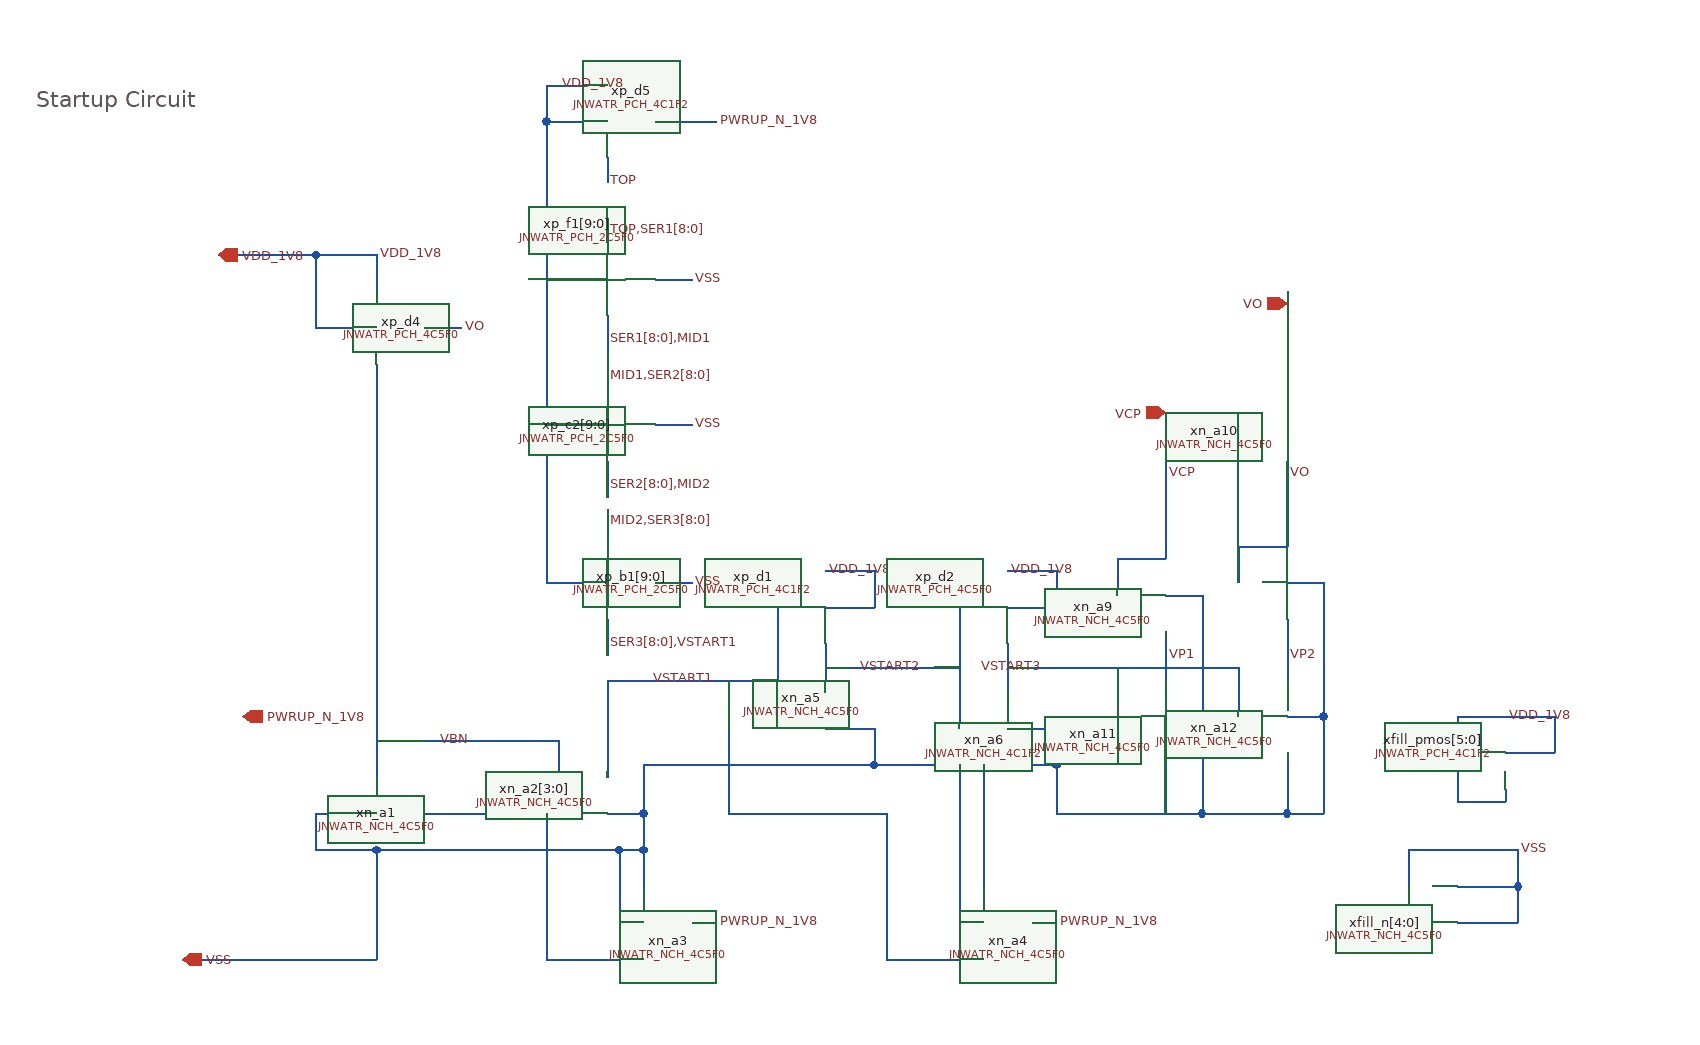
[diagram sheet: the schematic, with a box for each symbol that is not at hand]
v {xschem version=3.4.7 file_version=1.2}
G {}
K {}
V {}
S {}
E {}
T {Startup Circuit} -180 -740 0 0 1 1 {}
N 290 -140 320 -140 {lab=VSS}
N 320 -140 320 -110 {lab=VSS}
N 250 -200 250 -140 {lab=VBN}
N 290 -240 290 -170 {lab=VSTART1}
N 470 -280 470 -240 {lab=VSTART2}
N 470 -210 510 -210 {lab=VSS}
N 510 -210 510 -180 {lab=VSS}
N 470 -180 510 -180 {lab=VSS}
N 320 -180 470 -180 {lab=VSS}
N 320 -180 320 -140 {lab=VSS}
N 430 -310 430 -210 {lab=VSTART1}
N 290 -250 430 -250 {lab=VSTART1}
N 470 -310 510 -310 {lab=VDD_1V8}
N 510 -340 510 -310 {lab=VDD_1V8}
N 470 -340 510 -340 {lab=VDD_1V8}
N 620 -280 620 -240 {lab=VSTART3}
N 620 -210 660 -210 {lab=VSS}
N 660 -210 660 -180 {lab=VSS}
N 620 -180 660 -180 {lab=VSS}
N 580 -310 580 -210 {lab=VSTART2}
N 620 -310 660 -310 {lab=VDD_1V8}
N 660 -340 660 -310 {lab=VDD_1V8}
N 620 -340 660 -340 {lab=VDD_1V8}
N 470 -260 580 -260 {lab=VSTART2}
N 660 -140 730 -140 {lab=VSS}
N 730 -140 760 -140 {lab=VSS}
N 850 -190 850 -140 {lab=VSS}
N 780 -140 850 -140 {lab=VSS}
N 850 -220 880 -220 {lab=VSS}
N 880 -220 880 -140 {lab=VSS}
N 850 -140 880 -140 {lab=VSS}
N 760 -140 780 -140 {lab=VSS}
N 690 -260 810 -260 {lab=VSTART3}
N 810 -260 810 -220 {lab=VSTART3}
N 660 -180 660 -140 {lab=VSS}
N 510 -180 620 -180 {lab=VSS}
N 240 -430 240 -380 {lab=VDD_1V8}
N 290 -680 290 -660 {lab=TOP}
N 330 -330 360 -330 {lab=VSS}
N 620 -260 690 -260 {lab=VSTART3}
N 140 -140 250 -140 {lab=VBN}
N 100 -510 100 -170 {lab=VBN}
N 50 -600 50 -540 {lab=VDD_1V8}
N 100 -600 100 -570 {lab=VDD_1V8}
N 100 -200 250 -200 {lab=VBN}
N 750 -220 780 -220 {lab=VSS}
N 780 -220 780 -140 {lab=VSS}
N 750 -190 750 -140 {lab=VSS}
N 710 -260 710 -220 {lab=VSTART3}
N 750 -420 750 -410 {lab=VCP}
N 50 -540 100 -540 {lab=VDD_1V8}
N 50 -600 100 -600 {lab=VDD_1V8}
N 70 -140 100 -140 {lab=VSS}
N 50 -140 70 -140 {lab=VSS}
N 50 -140 50 -110 {lab=VSS}
N 300 -110 300 -50 {lab=VSS}
N 300 -50 320 -50 {lab=VSS}
N 320 -110 320 -80 {lab=VSS}
N 360 -50 380 -50 {lab=PWRUP_N_1V8}
N 240 -20 320 -20 {lab=VBN}
N 240 -140 240 -20 {lab=VBN}
N 240 -710 290 -710 {lab=VDD_1V8}
N 240 -710 240 -680 {lab=VDD_1V8}
N 240 -740 240 -710 {lab=VDD_1V8}
N 240 -740 290 -740 {lab=VDD_1V8}
N 330 -710 380 -710 {lab=PWRUP_N_1V8}
N 580 -110 580 -50 {lab=VSS}
N 580 -50 600 -50 {lab=VSS}
N 600 -110 600 -80 {lab=VSS}
N 640 -50 660 -50 {lab=PWRUP_N_1V8}
N 520 -20 600 -20 {lab=VSTART1}
N 520 -140 520 -20 {lab=VSTART1}
N 600 -180 600 -110 {lab=VSS}
N 580 -180 580 -110 {lab=VSS}
N 390 -140 520 -140 {lab=VSTART1}
N 390 -250 390 -140 {lab=VSTART1}
N 750 -290 750 -250 {lab=VP1}
N 750 -320 780 -320 {lab=VSS}
N 780 -320 780 -220 {lab=VSS}
N 710 -350 710 -320 {lab=VCP}
N 710 -350 750 -350 {lab=VCP}
N 750 -410 750 -350 {lab=VCP}
N 850 -330 880 -330 {lab=VSS}
N 810 -360 810 -330 {lab=VO}
N 810 -360 850 -360 {lab=VO}
N 850 -300 850 -250 {lab=VP2}
N 880 -330 880 -220 {lab=VSS}
N 850 -420 850 -360 {lab=VO}
N -30 -600 30 -600 {lab=VDD_1V8}
N 850 -560 850 -420 {lab=VO}
N 50 -110 100 -110 {lab=VSS}
N 100 -110 100 -20 {lab=VSS}
N -60 -20 100 -20 {lab=VSS}
N 30 -600 50 -600 {lab=VDD_1V8}
N 850 -570 850 -560 {lab=VO}
N 270 -330 290 -330 {lab=VDD_1V8}
N 290 -390 290 -360 {lab=MID2,SER3[8:0]}
N 290 -300 290 -270 {lab=SER3[8:0],VSTART1}
N 290 -250 290 -240 {lab=VSTART1}
N 240 -380 240 -330 {lab=VDD_1V8}
N 240 -330 270 -330 {lab=VDD_1V8}
N 290 -110 300 -110 {lab=VSS}
N 100 -110 290 -110 {lab=VSS}
N 750 -470 750 -420 {lab=VCP}
N 140 -540 170 -540 {lab=VO}
N 240 -540 240 -430 {lab=VDD_1V8}
N 290 -510 290 -490 {lab=MID1,SER2[8:0]}
N 290 -430 290 -400 {lab=SER2[8:0],MID2}
N 330 -460 360 -460 {lab=VSS}
N 300 -110 320 -110 {lab=VSS}
N 240 -650 240 -540 {lab=VDD_1V8}
N 240 -680 240 -650 {lab=VDD_1V8}
N 290 -630 290 -610 {lab=TOP,SER1[8:0]}
N 290 -550 290 -520 {lab=SER1[8:0],MID1}
N 330 -580 360 -580 {lab=VSS}
N 240 -460 290 -460 {lab=VDD_1V8}
N 240 -580 290 -580 {lab=VDD_1V8}
N 1030 -190 1070 -190 {lab=VDD_1V8}
N 1070 -220 1070 -190 {lab=VDD_1V8}
N 1030 -220 1070 -220 {lab=VDD_1V8}
N 1030 -160 1030 -150 {lab=VDD_1V8}
N 990 -150 1030 -150 {lab=VDD_1V8}
N 990 -190 990 -150 {lab=VDD_1V8}
N 990 -220 990 -190 {lab=VDD_1V8}
N 990 -220 1030 -220 {lab=VDD_1V8}
N 990 -50 1040 -50 {lab=VSS}
N 1040 -80 1040 -50 {lab=VSS}
N 990 -80 1040 -80 {lab=VSS}
N 1040 -110 1040 -80 {lab=VSS}
N 990 -110 1040 -110 {lab=VSS}
N 950 -110 950 -80 {lab=VSS}
N 950 -110 990 -110 {lab=VSS}
C {JNW_ATR_SKY130A/JNWATR_NCH_4C5F0.sym} 250 -140 0 0 {name=xn_a2[3:0]}
C {JNW_ATR_SKY130A/JNWATR_NCH_4C5F0.sym} 430 -210 0 0 {name=xn_a5}
C {JNW_ATR_SKY130A/JNWATR_PCH_4C1F2.sym} 430 -310 0 0 {name=xp_d1}
C {devices/lab_wire.sym} 470 -340 0 1 {name=p43 sig_type=std_logic lab=VDD_1V8}
C {devices/lab_wire.sym} 380 -250 0 0 {name=p37 sig_type=std_logic lab=VSTART1}
C {JNW_ATR_SKY130A/JNWATR_NCH_4C1F2.sym} 580 -210 0 0 {name=xn_a6}
C {JNW_ATR_SKY130A/JNWATR_PCH_4C5F0.sym} 580 -310 0 0 {name=xp_d2}
C {devices/lab_wire.sym} 620 -340 0 1 {name=p44 sig_type=std_logic lab=VDD_1V8}
C {JNW_ATR_SKY130A/JNWATR_NCH_4C5F0.sym} 810 -220 0 0 {name=xn_a12}
C {devices/lab_wire.sym} 850 -420 0 1 {name=p52 sig_type=std_logic lab=VO}
C {devices/lab_wire.sym} 550 -260 0 0 {name=p54 sig_type=std_logic lab=VSTART2}
C {devices/lab_wire.sym} 650 -260 0 0 {name=p58 sig_type=std_logic lab=VSTART3}
C {devices/lab_wire.sym} 360 -330 0 1 {name=p36 sig_type=std_logic lab=VSS}
C {JNW_ATR_SKY130A/JNWATR_PCH_4C5F0.sym} 140 -540 0 1 {name=xp_d4}
C {JNW_ATR_SKY130A/JNWATR_NCH_4C5F0.sym} 140 -140 0 1 {name=xn_a1}
C {devices/lab_wire.sym} 170 -540 0 1 {name=p6 sig_type=std_logic lab=VO}
C {JNW_ATR_SKY130A/JNWATR_NCH_4C5F0.sym} 710 -220 0 0 {name=xn_a11}
C {devices/lab_wire.sym} 750 -420 0 1 {name=p56 sig_type=std_logic lab=VCP}
C {devices/lab_wire.sym} 100 -600 0 1 {name=p61 sig_type=std_logic lab=VDD_1V8}
C {JNW_ATR_SKY130A/JNWATR_NCH_4C5F0.sym} 360 -50 2 0 {name=xn_a3}
C {devices/lab_wire.sym} 380 -50 2 0 {name=p64 sig_type=std_logic lab=PWRUP_N_1V8}
C {JNW_ATR_SKY130A/JNWATR_PCH_4C1F2.sym} 330 -710 0 1 {name=xp_d5}
C {devices/lab_wire.sym} 250 -740 0 1 {name=p38 sig_type=std_logic lab=VDD_1V8}
C {devices/lab_wire.sym} 380 -710 0 1 {name=p65 sig_type=std_logic lab=PWRUP_N_1V8}
C {JNW_ATR_SKY130A/JNWATR_NCH_4C5F0.sym} 640 -50 2 0 {name=xn_a4}
C {devices/lab_wire.sym} 660 -50 2 0 {name=p66 sig_type=std_logic lab=PWRUP_N_1V8}
C {JNW_ATR_SKY130A/JNWATR_NCH_4C5F0.sym} 710 -320 0 0 {name=xn_a9}
C {JNW_ATR_SKY130A/JNWATR_NCH_4C5F0.sym} 810 -330 0 0 {name=xn_a10}
C {devices/ipin.sym} -30 -600 2 1 {name=p4 lab=VDD_1V8}
C {devices/ipin.sym} -60 -20 2 1 {name=p5 lab=VSS}
C {devices/ipin.sym} -10 -220 2 1 {name=p9 lab=PWRUP_N_1V8}
C {devices/ipin.sym} 850 -560 0 0 {name=p25 lab=VO}
C {devices/ipin.sym} 750 -470 0 0 {name=p1 lab=VCP}
C {devices/lab_wire.sym} 290 -380 0 1 {name=p2 sig_type=std_logic lab=MID2,SER3[8:0]}
C {devices/lab_wire.sym} 290 -280 0 1 {name=p3 sig_type=std_logic lab=SER3[8:0],VSTART1}
C {devices/lab_wire.sym} 290 -660 0 1 {name=p7 sig_type=std_logic lab=TOP}
C {JNW_ATR_SKY130A/JNWATR_PCH_2C5F0.sym} 330 -330 0 1 {name=xp_b1[9:0]}
C {JNW_ATR_SKY130A/JNWATR_PCH_2C5F0.sym} 330 -460 0 1 {name=xp_c2[9:0]}
C {devices/lab_wire.sym} 290 -500 0 1 {name=p8 sig_type=std_logic lab=MID1,SER2[8:0]}
C {devices/lab_wire.sym} 290 -410 0 1 {name=p10 sig_type=std_logic lab=SER2[8:0],MID2}
C {devices/lab_wire.sym} 360 -460 0 1 {name=p11 sig_type=std_logic lab=VSS}
C {devices/lab_wire.sym} 150 -200 0 1 {name=p12 sig_type=std_logic lab=VBN}
C {devices/lab_wire.sym} 750 -270 0 1 {name=p13 sig_type=std_logic lab=VP1}
C {devices/lab_wire.sym} 850 -270 0 1 {name=p14 sig_type=std_logic lab=VP2}
C {JNW_ATR_SKY130A/JNWATR_PCH_2C5F0.sym} 330 -580 0 1 {name=xp_f1[9:0]}
C {devices/lab_wire.sym} 290 -620 0 1 {name=p15 sig_type=std_logic lab=TOP,SER1[8:0]}
C {devices/lab_wire.sym} 290 -530 0 1 {name=p16 sig_type=std_logic lab=SER1[8:0],MID1}
C {devices/lab_wire.sym} 360 -580 0 1 {name=p17 sig_type=std_logic lab=VSS}
C {JNW_ATR_SKY130A/JNWATR_PCH_4C1F2.sym} 990 -190 0 0 {name=xfill_pmos[5:0]}
C {devices/lab_wire.sym} 1030 -220 0 1 {name=p18 sig_type=std_logic lab=VDD_1V8}
C {JNW_ATR_SKY130A/JNWATR_NCH_4C5F0.sym} 950 -80 0 0 {name=xfill_n[4:0]}
C {devices/lab_wire.sym} 1040 -110 0 1 {name=p19 sig_type=std_logic lab=VSS}
